VERSION 5.7 ;
  NOWIREEXTENSIONATPIN ON ;
  DIVIDERCHAR "/" ;
  BUSBITCHARS "[]" ;
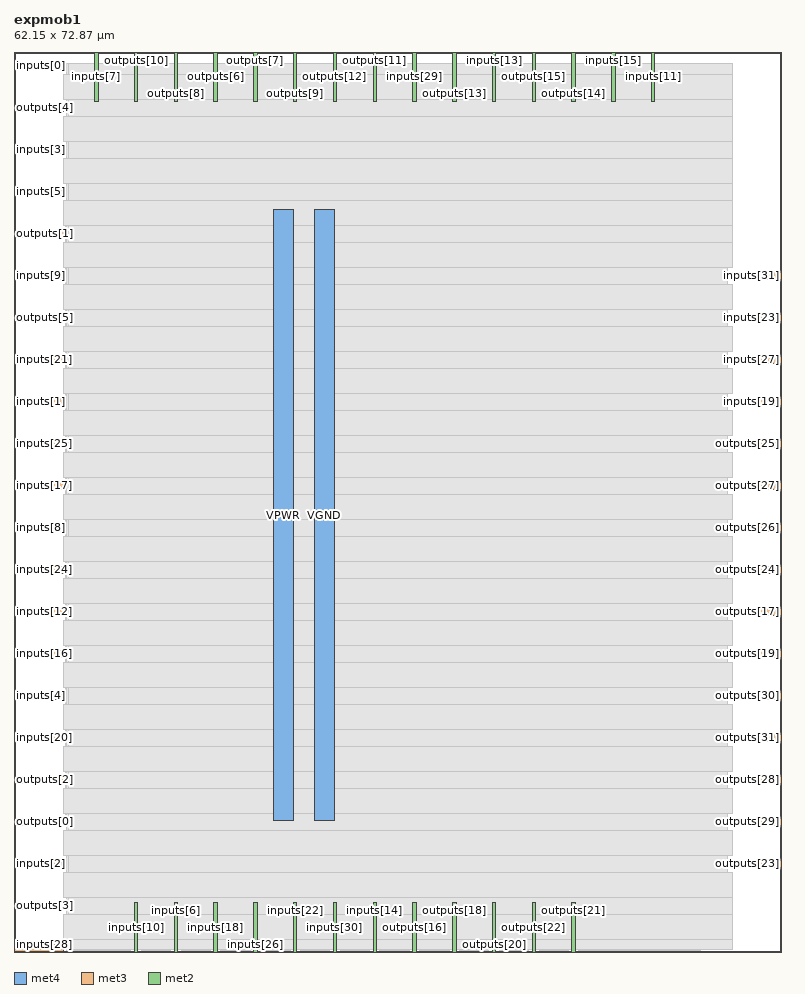
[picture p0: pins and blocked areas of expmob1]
MACRO expmob1
  CLASS BLOCK ;
  FOREIGN expmob1 ;
  ORIGIN 0.000 0.000 ;
  SIZE 62.150 BY 72.870 ;
  PIN VGND
    DIRECTION INOUT ;
    USE GROUND ;
    PORT
      LAYER met4 ;
        RECT 24.340 10.640 25.940 60.080 ;
    END
  END VGND
  PIN VPWR
    DIRECTION INOUT ;
    USE POWER ;
    PORT
      LAYER met4 ;
        RECT 21.040 10.640 22.640 60.080 ;
    END
  END VPWR
  PIN inputs[0]
    DIRECTION INPUT ;
    USE SIGNAL ;
    ANTENNAGATEAREA 0.247500 ;
    PORT
      LAYER met3 ;
        RECT 0.000 71.440 4.000 72.040 ;
    END
  END inputs[0]
  PIN inputs[10]
    DIRECTION INPUT ;
    USE SIGNAL ;
    ANTENNAGATEAREA 0.196500 ;
    PORT
      LAYER met2 ;
        RECT 9.750 0.000 10.030 4.000 ;
    END
  END inputs[10]
  PIN inputs[11]
    DIRECTION INPUT ;
    USE SIGNAL ;
    ANTENNAGATEAREA 0.196500 ;
    PORT
      LAYER met2 ;
        RECT 51.610 68.870 51.890 72.870 ;
    END
  END inputs[11]
  PIN inputs[12]
    DIRECTION INPUT ;
    USE SIGNAL ;
    ANTENNAGATEAREA 0.196500 ;
    PORT
      LAYER met3 ;
        RECT 0.000 27.240 4.000 27.840 ;
    END
  END inputs[12]
  PIN inputs[13]
    DIRECTION INPUT ;
    USE SIGNAL ;
    ANTENNAGATEAREA 0.196500 ;
    PORT
      LAYER met2 ;
        RECT 38.730 68.870 39.010 72.870 ;
    END
  END inputs[13]
  PIN inputs[14]
    DIRECTION INPUT ;
    USE SIGNAL ;
    ANTENNAGATEAREA 0.196500 ;
    PORT
      LAYER met2 ;
        RECT 29.070 0.000 29.350 4.000 ;
    END
  END inputs[14]
  PIN inputs[15]
    DIRECTION INPUT ;
    USE SIGNAL ;
    ANTENNAGATEAREA 0.196500 ;
    PORT
      LAYER met2 ;
        RECT 48.390 68.870 48.670 72.870 ;
    END
  END inputs[15]
  PIN inputs[16]
    DIRECTION INPUT ;
    USE SIGNAL ;
    ANTENNAGATEAREA 0.213000 ;
    PORT
      LAYER met3 ;
        RECT 0.000 23.840 4.000 24.440 ;
    END
  END inputs[16]
  PIN inputs[17]
    DIRECTION INPUT ;
    USE SIGNAL ;
    ANTENNAGATEAREA 0.213000 ;
    PORT
      LAYER met3 ;
        RECT 0.000 37.440 4.000 38.040 ;
    END
  END inputs[17]
  PIN inputs[18]
    DIRECTION INPUT ;
    USE SIGNAL ;
    ANTENNAGATEAREA 0.196500 ;
    PORT
      LAYER met2 ;
        RECT 16.190 0.000 16.470 4.000 ;
    END
  END inputs[18]
  PIN inputs[19]
    DIRECTION INPUT ;
    USE SIGNAL ;
    ANTENNAGATEAREA 0.196500 ;
    PORT
      LAYER met3 ;
        RECT 58.150 44.240 62.150 44.840 ;
    END
  END inputs[19]
  PIN inputs[1]
    DIRECTION INPUT ;
    USE SIGNAL ;
    ANTENNAGATEAREA 0.213000 ;
    PORT
      LAYER met3 ;
        RECT 0.000 44.240 4.000 44.840 ;
    END
  END inputs[1]
  PIN inputs[20]
    DIRECTION INPUT ;
    USE SIGNAL ;
    ANTENNAGATEAREA 0.196500 ;
    PORT
      LAYER met3 ;
        RECT 0.000 17.040 4.000 17.640 ;
    END
  END inputs[20]
  PIN inputs[21]
    DIRECTION INPUT ;
    USE SIGNAL ;
    ANTENNAGATEAREA 0.196500 ;
    PORT
      LAYER met3 ;
        RECT 0.000 47.640 4.000 48.240 ;
    END
  END inputs[21]
  PIN inputs[22]
    DIRECTION INPUT ;
    USE SIGNAL ;
    ANTENNAGATEAREA 0.196500 ;
    PORT
      LAYER met2 ;
        RECT 22.630 0.000 22.910 4.000 ;
    END
  END inputs[22]
  PIN inputs[23]
    DIRECTION INPUT ;
    USE SIGNAL ;
    ANTENNAGATEAREA 0.196500 ;
    PORT
      LAYER met3 ;
        RECT 58.150 51.040 62.150 51.640 ;
    END
  END inputs[23]
  PIN inputs[24]
    DIRECTION INPUT ;
    USE SIGNAL ;
    ANTENNAGATEAREA 0.196500 ;
    PORT
      LAYER met3 ;
        RECT 0.000 30.640 4.000 31.240 ;
    END
  END inputs[24]
  PIN inputs[25]
    DIRECTION INPUT ;
    USE SIGNAL ;
    ANTENNAGATEAREA 0.196500 ;
    PORT
      LAYER met3 ;
        RECT 0.000 40.840 4.000 41.440 ;
    END
  END inputs[25]
  PIN inputs[26]
    DIRECTION INPUT ;
    USE SIGNAL ;
    ANTENNAGATEAREA 0.196500 ;
    PORT
      LAYER met2 ;
        RECT 19.410 0.000 19.690 4.000 ;
    END
  END inputs[26]
  PIN inputs[27]
    DIRECTION INPUT ;
    USE SIGNAL ;
    ANTENNAGATEAREA 0.196500 ;
    PORT
      LAYER met3 ;
        RECT 58.150 47.640 62.150 48.240 ;
    END
  END inputs[27]
  PIN inputs[28]
    DIRECTION INPUT ;
    USE SIGNAL ;
    ANTENNAGATEAREA 0.196500 ;
    PORT
      LAYER met3 ;
        RECT 0.000 0.040 4.000 0.640 ;
    END
  END inputs[28]
  PIN inputs[29]
    DIRECTION INPUT ;
    USE SIGNAL ;
    ANTENNAGATEAREA 0.196500 ;
    PORT
      LAYER met2 ;
        RECT 32.290 68.870 32.570 72.870 ;
    END
  END inputs[29]
  PIN inputs[2]
    DIRECTION INPUT ;
    USE SIGNAL ;
    ANTENNAGATEAREA 0.159000 ;
    PORT
      LAYER met3 ;
        RECT 0.000 6.840 4.000 7.440 ;
    END
  END inputs[2]
  PIN inputs[30]
    DIRECTION INPUT ;
    USE SIGNAL ;
    ANTENNAGATEAREA 0.196500 ;
    PORT
      LAYER met2 ;
        RECT 25.850 0.000 26.130 4.000 ;
    END
  END inputs[30]
  PIN inputs[31]
    DIRECTION INPUT ;
    USE SIGNAL ;
    ANTENNAGATEAREA 0.196500 ;
    PORT
      LAYER met3 ;
        RECT 58.150 54.440 62.150 55.040 ;
    END
  END inputs[31]
  PIN inputs[3]
    DIRECTION INPUT ;
    USE SIGNAL ;
    ANTENNAGATEAREA 0.159000 ;
    PORT
      LAYER met3 ;
        RECT 0.000 64.640 4.000 65.240 ;
    END
  END inputs[3]
  PIN inputs[4]
    DIRECTION INPUT ;
    USE SIGNAL ;
    ANTENNAGATEAREA 0.213000 ;
    PORT
      LAYER met3 ;
        RECT 0.000 20.440 4.000 21.040 ;
    END
  END inputs[4]
  PIN inputs[5]
    DIRECTION INPUT ;
    USE SIGNAL ;
    ANTENNAGATEAREA 0.126000 ;
    PORT
      LAYER met3 ;
        RECT 0.000 61.240 4.000 61.840 ;
    END
  END inputs[5]
  PIN inputs[6]
    DIRECTION INPUT ;
    USE SIGNAL ;
    ANTENNAGATEAREA 0.213000 ;
    PORT
      LAYER met2 ;
        RECT 12.970 0.000 13.250 4.000 ;
    END
  END inputs[6]
  PIN inputs[7]
    DIRECTION INPUT ;
    USE SIGNAL ;
    ANTENNAGATEAREA 0.126000 ;
    PORT
      LAYER met2 ;
        RECT 6.530 68.870 6.810 72.870 ;
    END
  END inputs[7]
  PIN inputs[8]
    DIRECTION INPUT ;
    USE SIGNAL ;
    ANTENNAGATEAREA 0.213000 ;
    PORT
      LAYER met3 ;
        RECT 0.000 34.040 4.000 34.640 ;
    END
  END inputs[8]
  PIN inputs[9]
    DIRECTION INPUT ;
    USE SIGNAL ;
    ANTENNAGATEAREA 0.213000 ;
    PORT
      LAYER met3 ;
        RECT 0.000 54.440 4.000 55.040 ;
    END
  END inputs[9]
  PIN outputs[0]
    DIRECTION OUTPUT ;
    USE SIGNAL ;
    ANTENNADIFFAREA 0.445500 ;
    PORT
      LAYER met3 ;
        RECT 0.000 10.240 4.000 10.840 ;
    END
  END outputs[0]
  PIN outputs[10]
    DIRECTION OUTPUT ;
    USE SIGNAL ;
    ANTENNADIFFAREA 0.445500 ;
    PORT
      LAYER met2 ;
        RECT 9.750 68.870 10.030 72.870 ;
    END
  END outputs[10]
  PIN outputs[11]
    DIRECTION OUTPUT ;
    USE SIGNAL ;
    ANTENNADIFFAREA 0.445500 ;
    PORT
      LAYER met2 ;
        RECT 29.070 68.870 29.350 72.870 ;
    END
  END outputs[11]
  PIN outputs[12]
    DIRECTION OUTPUT ;
    USE SIGNAL ;
    ANTENNADIFFAREA 0.445500 ;
    PORT
      LAYER met2 ;
        RECT 25.850 68.870 26.130 72.870 ;
    END
  END outputs[12]
  PIN outputs[13]
    DIRECTION OUTPUT ;
    USE SIGNAL ;
    ANTENNADIFFAREA 0.445500 ;
    PORT
      LAYER met2 ;
        RECT 35.510 68.870 35.790 72.870 ;
    END
  END outputs[13]
  PIN outputs[14]
    DIRECTION OUTPUT ;
    USE SIGNAL ;
    ANTENNADIFFAREA 0.445500 ;
    PORT
      LAYER met2 ;
        RECT 45.170 68.870 45.450 72.870 ;
    END
  END outputs[14]
  PIN outputs[15]
    DIRECTION OUTPUT ;
    USE SIGNAL ;
    ANTENNADIFFAREA 0.445500 ;
    PORT
      LAYER met2 ;
        RECT 41.950 68.870 42.230 72.870 ;
    END
  END outputs[15]
  PIN outputs[16]
    DIRECTION OUTPUT ;
    USE SIGNAL ;
    ANTENNADIFFAREA 0.445500 ;
    PORT
      LAYER met2 ;
        RECT 32.290 0.000 32.570 4.000 ;
    END
  END outputs[16]
  PIN outputs[17]
    DIRECTION OUTPUT ;
    USE SIGNAL ;
    ANTENNADIFFAREA 0.445500 ;
    PORT
      LAYER met3 ;
        RECT 58.150 27.240 62.150 27.840 ;
    END
  END outputs[17]
  PIN outputs[18]
    DIRECTION OUTPUT ;
    USE SIGNAL ;
    ANTENNADIFFAREA 0.445500 ;
    PORT
      LAYER met2 ;
        RECT 35.510 0.000 35.790 4.000 ;
    END
  END outputs[18]
  PIN outputs[19]
    DIRECTION OUTPUT ;
    USE SIGNAL ;
    ANTENNADIFFAREA 0.445500 ;
    PORT
      LAYER met3 ;
        RECT 58.150 23.840 62.150 24.440 ;
    END
  END outputs[19]
  PIN outputs[1]
    DIRECTION OUTPUT ;
    USE SIGNAL ;
    ANTENNADIFFAREA 0.445500 ;
    PORT
      LAYER met3 ;
        RECT 0.000 57.840 4.000 58.440 ;
    END
  END outputs[1]
  PIN outputs[20]
    DIRECTION OUTPUT ;
    USE SIGNAL ;
    ANTENNADIFFAREA 0.445500 ;
    PORT
      LAYER met2 ;
        RECT 38.730 0.000 39.010 4.000 ;
    END
  END outputs[20]
  PIN outputs[21]
    DIRECTION OUTPUT ;
    USE SIGNAL ;
    ANTENNADIFFAREA 0.445500 ;
    PORT
      LAYER met2 ;
        RECT 45.170 0.000 45.450 4.000 ;
    END
  END outputs[21]
  PIN outputs[22]
    DIRECTION OUTPUT ;
    USE SIGNAL ;
    ANTENNADIFFAREA 0.445500 ;
    PORT
      LAYER met2 ;
        RECT 41.950 0.000 42.230 4.000 ;
    END
  END outputs[22]
  PIN outputs[23]
    DIRECTION OUTPUT ;
    USE SIGNAL ;
    ANTENNADIFFAREA 0.445500 ;
    PORT
      LAYER met3 ;
        RECT 58.150 6.840 62.150 7.440 ;
    END
  END outputs[23]
  PIN outputs[24]
    DIRECTION OUTPUT ;
    USE SIGNAL ;
    ANTENNADIFFAREA 0.445500 ;
    PORT
      LAYER met3 ;
        RECT 58.150 30.640 62.150 31.240 ;
    END
  END outputs[24]
  PIN outputs[25]
    DIRECTION OUTPUT ;
    USE SIGNAL ;
    ANTENNADIFFAREA 0.445500 ;
    PORT
      LAYER met3 ;
        RECT 58.150 40.840 62.150 41.440 ;
    END
  END outputs[25]
  PIN outputs[26]
    DIRECTION OUTPUT ;
    USE SIGNAL ;
    ANTENNADIFFAREA 0.445500 ;
    PORT
      LAYER met3 ;
        RECT 58.150 34.040 62.150 34.640 ;
    END
  END outputs[26]
  PIN outputs[27]
    DIRECTION OUTPUT ;
    USE SIGNAL ;
    ANTENNADIFFAREA 0.445500 ;
    PORT
      LAYER met3 ;
        RECT 58.150 37.440 62.150 38.040 ;
    END
  END outputs[27]
  PIN outputs[28]
    DIRECTION OUTPUT ;
    USE SIGNAL ;
    ANTENNADIFFAREA 0.445500 ;
    PORT
      LAYER met3 ;
        RECT 58.150 13.640 62.150 14.240 ;
    END
  END outputs[28]
  PIN outputs[29]
    DIRECTION OUTPUT ;
    USE SIGNAL ;
    ANTENNADIFFAREA 0.445500 ;
    PORT
      LAYER met3 ;
        RECT 58.150 10.240 62.150 10.840 ;
    END
  END outputs[29]
  PIN outputs[2]
    DIRECTION OUTPUT ;
    USE SIGNAL ;
    ANTENNADIFFAREA 0.445500 ;
    PORT
      LAYER met3 ;
        RECT 0.000 13.640 4.000 14.240 ;
    END
  END outputs[2]
  PIN outputs[30]
    DIRECTION OUTPUT ;
    USE SIGNAL ;
    ANTENNADIFFAREA 0.445500 ;
    PORT
      LAYER met3 ;
        RECT 58.150 20.440 62.150 21.040 ;
    END
  END outputs[30]
  PIN outputs[31]
    DIRECTION OUTPUT ;
    USE SIGNAL ;
    ANTENNADIFFAREA 0.445500 ;
    PORT
      LAYER met3 ;
        RECT 58.150 17.040 62.150 17.640 ;
    END
  END outputs[31]
  PIN outputs[3]
    DIRECTION OUTPUT ;
    USE SIGNAL ;
    ANTENNADIFFAREA 0.445500 ;
    PORT
      LAYER met3 ;
        RECT 0.000 3.440 4.000 4.040 ;
    END
  END outputs[3]
  PIN outputs[4]
    DIRECTION OUTPUT ;
    USE SIGNAL ;
    ANTENNADIFFAREA 0.445500 ;
    PORT
      LAYER met3 ;
        RECT 0.000 68.040 4.000 68.640 ;
    END
  END outputs[4]
  PIN outputs[5]
    DIRECTION OUTPUT ;
    USE SIGNAL ;
    ANTENNADIFFAREA 0.445500 ;
    PORT
      LAYER met3 ;
        RECT 0.000 51.040 4.000 51.640 ;
    END
  END outputs[5]
  PIN outputs[6]
    DIRECTION OUTPUT ;
    USE SIGNAL ;
    ANTENNADIFFAREA 0.445500 ;
    PORT
      LAYER met2 ;
        RECT 16.190 68.870 16.470 72.870 ;
    END
  END outputs[6]
  PIN outputs[7]
    DIRECTION OUTPUT ;
    USE SIGNAL ;
    ANTENNADIFFAREA 0.445500 ;
    PORT
      LAYER met2 ;
        RECT 19.410 68.870 19.690 72.870 ;
    END
  END outputs[7]
  PIN outputs[8]
    DIRECTION OUTPUT ;
    USE SIGNAL ;
    ANTENNADIFFAREA 0.445500 ;
    PORT
      LAYER met2 ;
        RECT 12.970 68.870 13.250 72.870 ;
    END
  END outputs[8]
  PIN outputs[9]
    DIRECTION OUTPUT ;
    USE SIGNAL ;
    ANTENNADIFFAREA 0.445500 ;
    PORT
      LAYER met2 ;
        RECT 22.630 68.870 22.910 72.870 ;
    END
  END outputs[9]
  OBS
      LAYER nwell ;
        RECT 5.330 10.795 56.770 59.925 ;
      LAYER li1 ;
        RECT 5.520 10.795 56.580 59.925 ;
      LAYER met1 ;
        RECT 4.210 10.640 56.580 60.080 ;
      LAYER met2 ;
        RECT 4.230 68.590 6.250 71.925 ;
        RECT 7.090 68.590 9.470 71.925 ;
        RECT 10.310 68.590 12.690 71.925 ;
        RECT 13.530 68.590 15.910 71.925 ;
        RECT 16.750 68.590 19.130 71.925 ;
        RECT 19.970 68.590 22.350 71.925 ;
        RECT 23.190 68.590 25.570 71.925 ;
        RECT 26.410 68.590 28.790 71.925 ;
        RECT 29.630 68.590 32.010 71.925 ;
        RECT 32.850 68.590 35.230 71.925 ;
        RECT 36.070 68.590 38.450 71.925 ;
        RECT 39.290 68.590 41.670 71.925 ;
        RECT 42.510 68.590 44.890 71.925 ;
        RECT 45.730 68.590 48.110 71.925 ;
        RECT 48.950 68.590 51.330 71.925 ;
        RECT 52.170 68.590 55.570 71.925 ;
        RECT 4.230 4.280 55.570 68.590 ;
        RECT 4.230 0.155 9.470 4.280 ;
        RECT 10.310 0.155 12.690 4.280 ;
        RECT 13.530 0.155 15.910 4.280 ;
        RECT 16.750 0.155 19.130 4.280 ;
        RECT 19.970 0.155 22.350 4.280 ;
        RECT 23.190 0.155 25.570 4.280 ;
        RECT 26.410 0.155 28.790 4.280 ;
        RECT 29.630 0.155 32.010 4.280 ;
        RECT 32.850 0.155 35.230 4.280 ;
        RECT 36.070 0.155 38.450 4.280 ;
        RECT 39.290 0.155 41.670 4.280 ;
        RECT 42.510 0.155 44.890 4.280 ;
        RECT 45.730 0.155 55.570 4.280 ;
      LAYER met3 ;
        RECT 4.400 71.040 58.150 71.905 ;
        RECT 3.990 69.040 58.150 71.040 ;
        RECT 4.400 67.640 58.150 69.040 ;
        RECT 3.990 65.640 58.150 67.640 ;
        RECT 4.400 64.240 58.150 65.640 ;
        RECT 3.990 62.240 58.150 64.240 ;
        RECT 4.400 60.840 58.150 62.240 ;
        RECT 3.990 58.840 58.150 60.840 ;
        RECT 4.400 57.440 58.150 58.840 ;
        RECT 3.990 55.440 58.150 57.440 ;
        RECT 4.400 54.040 57.750 55.440 ;
        RECT 3.990 52.040 58.150 54.040 ;
        RECT 4.400 50.640 57.750 52.040 ;
        RECT 3.990 48.640 58.150 50.640 ;
        RECT 4.400 47.240 57.750 48.640 ;
        RECT 3.990 45.240 58.150 47.240 ;
        RECT 4.400 43.840 57.750 45.240 ;
        RECT 3.990 41.840 58.150 43.840 ;
        RECT 4.400 40.440 57.750 41.840 ;
        RECT 3.990 38.440 58.150 40.440 ;
        RECT 4.400 37.040 57.750 38.440 ;
        RECT 3.990 35.040 58.150 37.040 ;
        RECT 4.400 33.640 57.750 35.040 ;
        RECT 3.990 31.640 58.150 33.640 ;
        RECT 4.400 30.240 57.750 31.640 ;
        RECT 3.990 28.240 58.150 30.240 ;
        RECT 4.400 26.840 57.750 28.240 ;
        RECT 3.990 24.840 58.150 26.840 ;
        RECT 4.400 23.440 57.750 24.840 ;
        RECT 3.990 21.440 58.150 23.440 ;
        RECT 4.400 20.040 57.750 21.440 ;
        RECT 3.990 18.040 58.150 20.040 ;
        RECT 4.400 16.640 57.750 18.040 ;
        RECT 3.990 14.640 58.150 16.640 ;
        RECT 4.400 13.240 57.750 14.640 ;
        RECT 3.990 11.240 58.150 13.240 ;
        RECT 4.400 9.840 57.750 11.240 ;
        RECT 3.990 7.840 58.150 9.840 ;
        RECT 4.400 6.440 57.750 7.840 ;
        RECT 3.990 4.440 58.150 6.440 ;
        RECT 4.400 3.040 58.150 4.440 ;
        RECT 3.990 1.040 58.150 3.040 ;
        RECT 4.400 0.175 58.150 1.040 ;
  END
END expmob1
END LIBRARY

